One B-rep face of a CAD part: STEP entity #1031.
In plain terms, the planar face has unit normal (0, -1, 0).
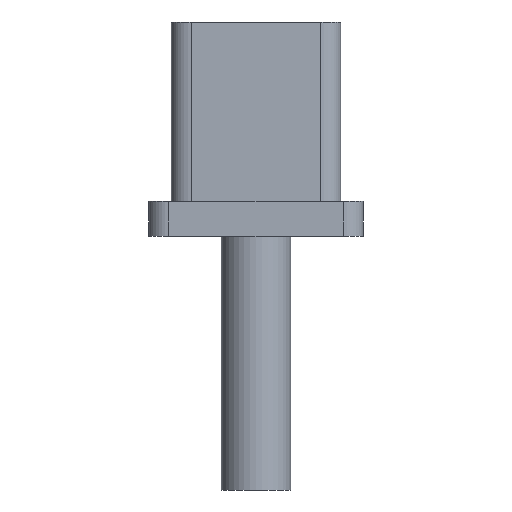
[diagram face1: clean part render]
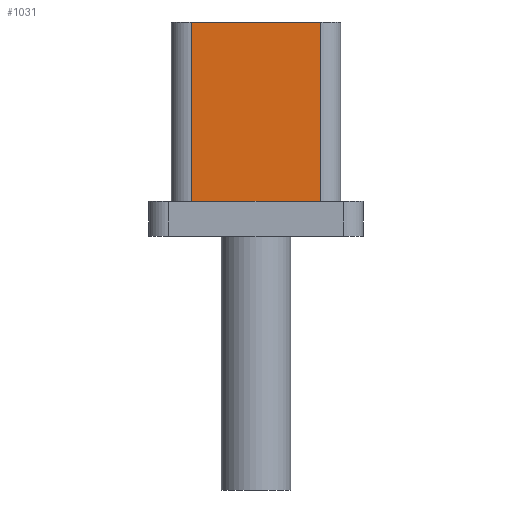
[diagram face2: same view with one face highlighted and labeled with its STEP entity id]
Its self-contained STEP definition (entity closure, numbers rounded to 3 decimals):
#44 = PLANE('',#45);
#45 = AXIS2_PLACEMENT_3D('',#46,#47,#48);
#46 = CARTESIAN_POINT('',(23.758,36.782,23.9));
#47 = DIRECTION('',(0.,0.,1.));
#48 = DIRECTION('',(1.,0.,0.));
#343 = VERTEX_POINT('',#344);
#344 = CARTESIAN_POINT('',(25.458,37.682,23.9));
#359 = CYLINDRICAL_SURFACE('',#360,0.8);
#360 = AXIS2_PLACEMENT_3D('',#361,#362,#363);
#361 = CARTESIAN_POINT('',(25.458,38.482,23.9));
#362 = DIRECTION('',(0.,0.,1.));
#363 = DIRECTION('',(-1.,-0.,0.));
#518 = VERTEX_POINT('',#519);
#519 = CARTESIAN_POINT('',(30.658,37.682,23.9));
#538 = CYLINDRICAL_SURFACE('',#539,0.8);
#539 = AXIS2_PLACEMENT_3D('',#540,#541,#542);
#540 = CARTESIAN_POINT('',(30.658,38.482,23.9));
#541 = DIRECTION('',(0.,0.,1.));
#542 = DIRECTION('',(1.,0.,-0.));
#550 = EDGE_CURVE('',#343,#518,#551,.T.);
#551 = SURFACE_CURVE('',#552,(#556,#563),.PCURVE_S1.);
#552 = LINE('',#553,#554);
#553 = CARTESIAN_POINT('',(24.658,37.682,23.9));
#554 = VECTOR('',#555,1.);
#555 = DIRECTION('',(1.,0.,0.));
#556 = PCURVE('',#44,#557);
#557 = DEFINITIONAL_REPRESENTATION('',(#558),#562);
#558 = LINE('',#559,#560);
#559 = CARTESIAN_POINT('',(0.9,0.9));
#560 = VECTOR('',#561,1.);
#561 = DIRECTION('',(1.,0.));
#562 = ( GEOMETRIC_REPRESENTATION_CONTEXT(2) 
PARAMETRIC_REPRESENTATION_CONTEXT() REPRESENTATION_CONTEXT('2D SPACE',''
  ) );
#563 = PCURVE('',#564,#569);
#564 = PLANE('',#565);
#565 = AXIS2_PLACEMENT_3D('',#566,#567,#568);
#566 = CARTESIAN_POINT('',(24.658,37.682,23.9));
#567 = DIRECTION('',(0.,1.,0.));
#568 = DIRECTION('',(0.,0.,1.));
#569 = DEFINITIONAL_REPRESENTATION('',(#570),#574);
#570 = LINE('',#571,#572);
#571 = CARTESIAN_POINT('',(0.,0.));
#572 = VECTOR('',#573,1.);
#573 = DIRECTION('',(0.,1.));
#574 = ( GEOMETRIC_REPRESENTATION_CONTEXT(2) 
PARAMETRIC_REPRESENTATION_CONTEXT() REPRESENTATION_CONTEXT('2D SPACE',''
  ) );
#959 = EDGE_CURVE('',#343,#960,#962,.T.);
#960 = VERTEX_POINT('',#961);
#961 = CARTESIAN_POINT('',(25.458,37.682,31.1));
#962 = SURFACE_CURVE('',#963,(#967,#974),.PCURVE_S1.);
#963 = LINE('',#964,#965);
#964 = CARTESIAN_POINT('',(25.458,37.682,23.9));
#965 = VECTOR('',#966,1.);
#966 = DIRECTION('',(0.,0.,1.));
#967 = PCURVE('',#359,#968);
#968 = DEFINITIONAL_REPRESENTATION('',(#969),#973);
#969 = LINE('',#970,#971);
#970 = CARTESIAN_POINT('',(1.571,0.));
#971 = VECTOR('',#972,1.);
#972 = DIRECTION('',(0.,1.));
#973 = ( GEOMETRIC_REPRESENTATION_CONTEXT(2) 
PARAMETRIC_REPRESENTATION_CONTEXT() REPRESENTATION_CONTEXT('2D SPACE',''
  ) );
#974 = PCURVE('',#564,#975);
#975 = DEFINITIONAL_REPRESENTATION('',(#976),#980);
#976 = LINE('',#977,#978);
#977 = CARTESIAN_POINT('',(0.,0.8));
#978 = VECTOR('',#979,1.);
#979 = DIRECTION('',(1.,0.));
#980 = ( GEOMETRIC_REPRESENTATION_CONTEXT(2) 
PARAMETRIC_REPRESENTATION_CONTEXT() REPRESENTATION_CONTEXT('2D SPACE',''
  ) );
#999 = PLANE('',#1000);
#1000 = AXIS2_PLACEMENT_3D('',#1001,#1002,#1003);
#1001 = CARTESIAN_POINT('',(24.658,37.682,31.1));
#1002 = DIRECTION('',(0.,0.,1.));
#1003 = DIRECTION('',(1.,0.,0.));
#1031 = ADVANCED_FACE('',(#1032),#564,.F.);
#1032 = FACE_BOUND('',#1033,.F.);
#1033 = EDGE_LOOP('',(#1034,#1035,#1036,#1059));
#1034 = ORIENTED_EDGE('',*,*,#550,.F.);
#1035 = ORIENTED_EDGE('',*,*,#959,.T.);
#1036 = ORIENTED_EDGE('',*,*,#1037,.T.);
#1037 = EDGE_CURVE('',#960,#1038,#1040,.T.);
#1038 = VERTEX_POINT('',#1039);
#1039 = CARTESIAN_POINT('',(30.658,37.682,31.1));
#1040 = SURFACE_CURVE('',#1041,(#1045,#1052),.PCURVE_S1.);
#1041 = LINE('',#1042,#1043);
#1042 = CARTESIAN_POINT('',(24.658,37.682,31.1));
#1043 = VECTOR('',#1044,1.);
#1044 = DIRECTION('',(1.,0.,0.));
#1045 = PCURVE('',#564,#1046);
#1046 = DEFINITIONAL_REPRESENTATION('',(#1047),#1051);
#1047 = LINE('',#1048,#1049);
#1048 = CARTESIAN_POINT('',(7.2,0.));
#1049 = VECTOR('',#1050,1.);
#1050 = DIRECTION('',(0.,1.));
#1051 = ( GEOMETRIC_REPRESENTATION_CONTEXT(2) 
PARAMETRIC_REPRESENTATION_CONTEXT() REPRESENTATION_CONTEXT('2D SPACE',''
  ) );
#1052 = PCURVE('',#999,#1053);
#1053 = DEFINITIONAL_REPRESENTATION('',(#1054),#1058);
#1054 = LINE('',#1055,#1056);
#1055 = CARTESIAN_POINT('',(0.,0.));
#1056 = VECTOR('',#1057,1.);
#1057 = DIRECTION('',(1.,0.));
#1058 = ( GEOMETRIC_REPRESENTATION_CONTEXT(2) 
PARAMETRIC_REPRESENTATION_CONTEXT() REPRESENTATION_CONTEXT('2D SPACE',''
  ) );
#1059 = ORIENTED_EDGE('',*,*,#1060,.F.);
#1060 = EDGE_CURVE('',#518,#1038,#1061,.T.);
#1061 = SURFACE_CURVE('',#1062,(#1066,#1073),.PCURVE_S1.);
#1062 = LINE('',#1063,#1064);
#1063 = CARTESIAN_POINT('',(30.658,37.682,23.9));
#1064 = VECTOR('',#1065,1.);
#1065 = DIRECTION('',(0.,0.,1.));
#1066 = PCURVE('',#564,#1067);
#1067 = DEFINITIONAL_REPRESENTATION('',(#1068),#1072);
#1068 = LINE('',#1069,#1070);
#1069 = CARTESIAN_POINT('',(0.,6.));
#1070 = VECTOR('',#1071,1.);
#1071 = DIRECTION('',(1.,0.));
#1072 = ( GEOMETRIC_REPRESENTATION_CONTEXT(2) 
PARAMETRIC_REPRESENTATION_CONTEXT() REPRESENTATION_CONTEXT('2D SPACE',''
  ) );
#1073 = PCURVE('',#538,#1074);
#1074 = DEFINITIONAL_REPRESENTATION('',(#1075),#1079);
#1075 = LINE('',#1076,#1077);
#1076 = CARTESIAN_POINT('',(-1.571,0.));
#1077 = VECTOR('',#1078,1.);
#1078 = DIRECTION('',(-0.,1.));
#1079 = ( GEOMETRIC_REPRESENTATION_CONTEXT(2) 
PARAMETRIC_REPRESENTATION_CONTEXT() REPRESENTATION_CONTEXT('2D SPACE',''
  ) );
